One B-rep face of a CAD part: STEP entity #477.
In plain terms, the planar face has unit normal (1, 0, 0).
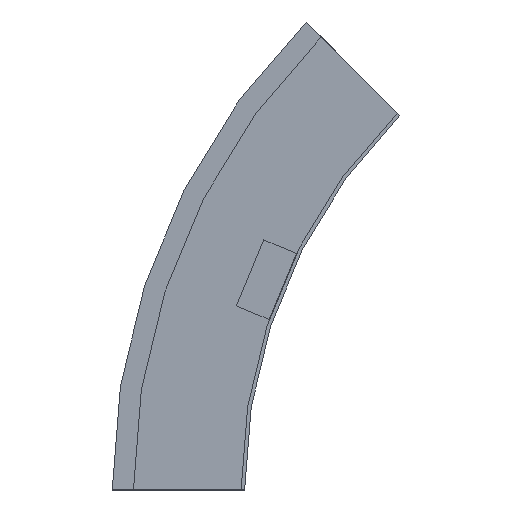
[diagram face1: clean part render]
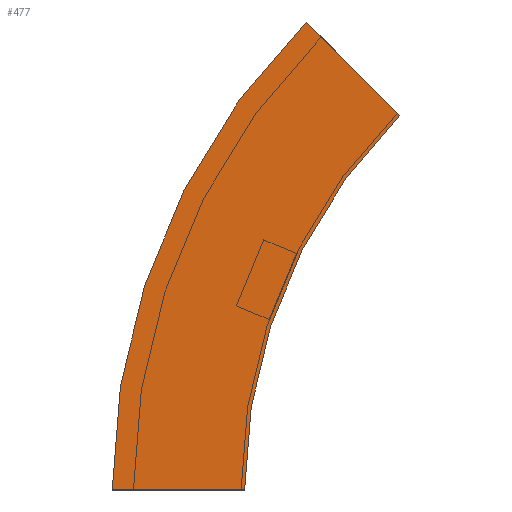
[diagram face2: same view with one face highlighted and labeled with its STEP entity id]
Its self-contained STEP definition (entity closure, numbers rounded to 3 decimals):
#9 = AXIS2_PLACEMENT_3D ( 'NONE', #232, #20, #144 ) ;
#20 = DIRECTION ( 'NONE',  ( 1., 0., 0. ) ) ;
#26 = DIRECTION ( 'NONE',  ( 0., 0.707, 0.707 ) ) ;
#35 = EDGE_CURVE ( 'NONE', #408, #310, #303, .T. ) ;
#51 = DIRECTION ( 'NONE',  ( 1., 0., 0. ) ) ;
#56 = CARTESIAN_POINT ( 'NONE',  ( 0., 0., 0. ) ) ;
#64 = CARTESIAN_POINT ( 'NONE',  ( 0., -87.868, 212.132 ) ) ;
#71 = EDGE_CURVE ( 'NONE', #133, #146, #376, .T. ) ;
#80 = DIRECTION ( 'NONE',  ( 1., 0., 0. ) ) ;
#87 = CARTESIAN_POINT ( 'NONE',  ( 0., 75., 0. ) ) ;
#133 = VERTEX_POINT ( 'NONE', #87 ) ;
#144 = DIRECTION ( 'NONE',  ( 0., 1., 0. ) ) ;
#146 = VERTEX_POINT ( 'NONE', #289 ) ;
#181 = AXIS2_PLACEMENT_3D ( 'NONE', #328, #80, #200 ) ;
#200 = DIRECTION ( 'NONE',  ( 0., 1., 0. ) ) ;
#205 = CARTESIAN_POINT ( 'NONE',  ( 0., 0., 0. ) ) ;
#207 = DIRECTION ( 'NONE',  ( 0., 1., 0. ) ) ;
#232 = CARTESIAN_POINT ( 'NONE',  ( 0., -300., 0. ) ) ;
#236 = LINE ( 'NONE', #497, #284 ) ;
#247 = AXIS2_PLACEMENT_3D ( 'NONE', #205, #51, #423 ) ;
#284 = VECTOR ( 'NONE', #26, 1000. ) ;
#289 = CARTESIAN_POINT ( 'NONE',  ( 0., -34.835, 265.165 ) ) ;
#303 = CIRCLE ( 'NONE', #9, 300. ) ;
#305 = ORIENTED_EDGE ( 'NONE', *, *, #522, .T. ) ;
#310 = VERTEX_POINT ( 'NONE', #64 ) ;
#318 = EDGE_CURVE ( 'NONE', #310, #146, #236, .T. ) ;
#320 = ORIENTED_EDGE ( 'NONE', *, *, #318, .F. ) ;
#328 = CARTESIAN_POINT ( 'NONE',  ( 0., -300., 0. ) ) ;
#349 = PLANE ( 'NONE',  #247 ) ;
#376 = CIRCLE ( 'NONE', #181, 375. ) ;
#408 = VERTEX_POINT ( 'NONE', #56 ) ;
#423 = DIRECTION ( 'NONE',  ( 0., 0., -1. ) ) ;
#425 = ORIENTED_EDGE ( 'NONE', *, *, #35, .F. ) ;
#430 = FACE_OUTER_BOUND ( 'NONE', #518, .T. ) ;
#435 = LINE ( 'NONE', #513, #450 ) ;
#450 = VECTOR ( 'NONE', #207, 1000. ) ;
#456 = ORIENTED_EDGE ( 'NONE', *, *, #71, .T. ) ;
#477 = ADVANCED_FACE ( 'NONE', ( #430 ), #349, .T. ) ;
#497 = CARTESIAN_POINT ( 'NONE',  ( 0., -87.868, 212.132 ) ) ;
#513 = CARTESIAN_POINT ( 'NONE',  ( 0., 0., 0. ) ) ;
#518 = EDGE_LOOP ( 'NONE', ( #456, #320, #425, #305 ) ) ;
#522 = EDGE_CURVE ( 'NONE', #408, #133, #435, .T. ) ;
